VERSION 5.7 ;
  NOWIREEXTENSIONATPIN ON ;
  DIVIDERCHAR "/" ;
  BUSBITCHARS "[]" ;
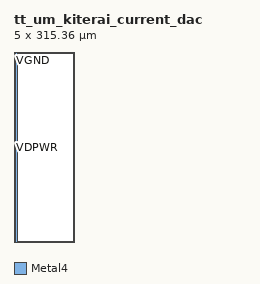
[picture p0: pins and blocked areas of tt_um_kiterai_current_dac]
MACRO tt_um_kiterai_current_dac
  CLASS BLOCK ;
  FOREIGN tt_um_kiterai_current_dac ;
  ORIGIN -1.000 -5.000 ;
  SIZE 5.000 BY 315.360 ;
  PIN VDPWR
    DIRECTION INOUT ;
    USE POWER ;
    PORT
      LAYER Metal4 ;
        RECT 1.000 5.000 3.000 320.360 ;
    END
  END VDPWR
  PIN VGND
    DIRECTION INOUT ;
    USE GROUND ;
    PORT
      LAYER Metal4 ;
        RECT 4.000 5.000 6.000 320.360 ;
    END
  END VGND
END tt_um_kiterai_current_dac
END LIBRARY

